VERSION 5.8 ;
BUSBITCHARS "[]" ;
DIVIDERCHAR "/" ;
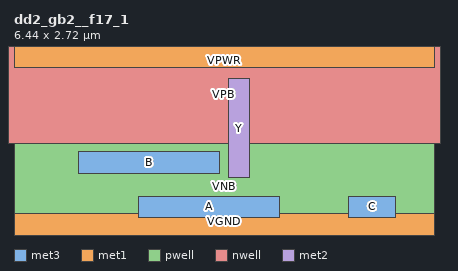
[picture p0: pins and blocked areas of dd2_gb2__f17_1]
MACRO dd2_gb2__f17_1
  CLASS CORE ;
  ORIGIN 0 0 ;
  SIZE 6.440 BY 2.720 ;
  SYMMETRY X Y ;
  SITE unithd ;
  PIN A
    DIRECTION INPUT ;
    USE SIGNAL ;
    ANTENNAGATEAREA 0.426000 ;
    PORT
      LAYER met3 ;
        RECT 1.905 0.175 4.075 0.505 ;
    END
  END A
  PIN B
    DIRECTION INPUT ;
    USE SIGNAL ;
    ANTENNAGATEAREA 0.426000 ;
    PORT
      LAYER met3 ;
        RECT 0.985 0.855 3.155 1.185 ;
    END
  END B
  PIN C
    DIRECTION INPUT ;
    USE SIGNAL ;
    ANTENNAGATEAREA 0.213000 ;
    PORT
      LAYER met3 ;
        RECT 5.125 0.175 5.855 0.505 ;
    END
  END C
  PIN VGND
    DIRECTION INOUT ;
    USE GROUND ;
    SHAPE ABUTMENT ;
    PORT
      LAYER met1 ;
        RECT 0.000 -0.240 6.440 0.240 ;
    END
  END VGND
  PIN VNB
    DIRECTION INOUT ;
    USE GROUND ;
    PORT
      LAYER pwell ;
        RECT 0.000 0.000 6.440 1.305 ;
    END
  END VNB
  PIN VPB
    DIRECTION INOUT ;
    USE POWER ;
    PORT
      LAYER nwell ;
        RECT -0.190 1.305 6.630 2.910 ;
    END
  END VPB
  PIN VPWR
    DIRECTION INOUT ;
    USE POWER ;
    SHAPE ABUTMENT ;
    PORT
      LAYER met1 ;
        RECT 0.000 2.480 6.440 2.960 ;
    END
  END VPWR
  PIN Y
    DIRECTION OUTPUT ;
    USE SIGNAL ;
    ANTENNADIFFAREA 1.286600 ;
    PORT
      LAYER met2 ;
        RECT 3.290 0.790 3.610 2.305 ;
    END
  END Y
  OBS
    LAYER li1 ;
      RECT 0.000 -0.085 6.440 0.085 ;
      RECT 0.605 0.085 0.775 0.565 ;
      RECT 2.445 0.085 2.615 0.565 ;
      RECT 1.445 0.255 1.775 0.710 ;
      RECT 4.205 0.255 4.535 0.710 ;
      RECT 5.585 0.255 5.915 0.710 ;
      RECT 1.065 0.380 1.235 1.075 ;
      RECT 0.985 1.075 1.315 1.245 ;
      RECT 1.985 0.380 2.155 1.075 ;
      RECT 1.905 1.075 2.235 1.245 ;
      RECT 2.905 0.380 3.075 1.075 ;
      RECT 2.825 1.075 3.155 1.245 ;
      RECT 3.825 0.380 3.995 1.075 ;
      RECT 3.745 1.075 4.075 1.245 ;
      RECT 5.205 0.380 5.375 1.075 ;
      RECT 5.125 1.075 5.455 1.245 ;
      RECT 2.365 1.505 2.695 2.465 ;
      RECT 3.285 1.505 3.615 2.465 ;
      RECT 4.665 1.505 4.995 2.465 ;
      RECT 0.605 1.495 0.775 2.635 ;
      RECT 5.665 1.495 5.835 2.635 ;
      RECT 0.000 2.635 6.440 2.805 ;
    LAYER met1 ;
      RECT 1.005 0.380 1.295 0.710 ;
      RECT 1.445 0.380 1.775 0.710 ;
      RECT 1.925 0.380 2.215 0.710 ;
      RECT 2.845 0.380 3.135 0.710 ;
      RECT 3.765 0.380 4.055 0.710 ;
      RECT 5.145 0.380 5.435 0.710 ;
      RECT 5.585 0.380 5.915 0.710 ;
      RECT 4.205 0.380 4.535 0.710 ;
      RECT 3.290 0.790 3.610 0.850 ;
      RECT 4.210 0.710 4.530 0.850 ;
      RECT 3.285 0.850 4.535 0.990 ;
      RECT 3.290 0.990 3.610 1.050 ;
      RECT 4.210 0.990 4.530 1.050 ;
      RECT 1.450 1.230 1.770 1.290 ;
      RECT 5.590 1.230 5.910 1.290 ;
      RECT 1.445 1.290 5.915 1.430 ;
      RECT 1.450 1.430 1.770 1.490 ;
      RECT 5.590 1.430 5.910 1.490 ;
      RECT 3.285 2.010 3.615 2.340 ;
      RECT 2.370 1.670 2.690 1.730 ;
      RECT 4.670 1.670 4.990 1.730 ;
      RECT 2.365 1.730 4.995 1.870 ;
      RECT 2.370 1.870 2.690 2.010 ;
      RECT 4.670 1.870 4.990 2.010 ;
      RECT 2.365 2.010 2.695 2.340 ;
      RECT 4.665 2.010 4.995 2.340 ;
    LAYER met2 ;
      RECT 1.930 0.155 2.210 0.210 ;
      RECT 1.910 0.210 2.230 0.675 ;
      RECT 3.770 0.155 4.050 0.210 ;
      RECT 3.750 0.210 4.070 0.675 ;
      RECT 5.150 0.155 5.430 0.210 ;
      RECT 5.130 0.210 5.450 0.675 ;
      RECT 4.210 0.415 4.530 1.050 ;
      RECT 0.990 0.415 1.310 1.150 ;
      RECT 1.010 1.150 1.290 1.205 ;
      RECT 2.830 0.415 3.150 1.150 ;
      RECT 2.850 1.150 3.130 1.205 ;
      RECT 1.450 0.415 1.770 1.490 ;
      RECT 5.590 0.415 5.910 1.490 ;
      RECT 2.370 1.670 2.690 2.305 ;
      RECT 4.670 1.670 4.990 2.305 ;
  END
END dd2_gb2__f17_1
END LIBRARY
